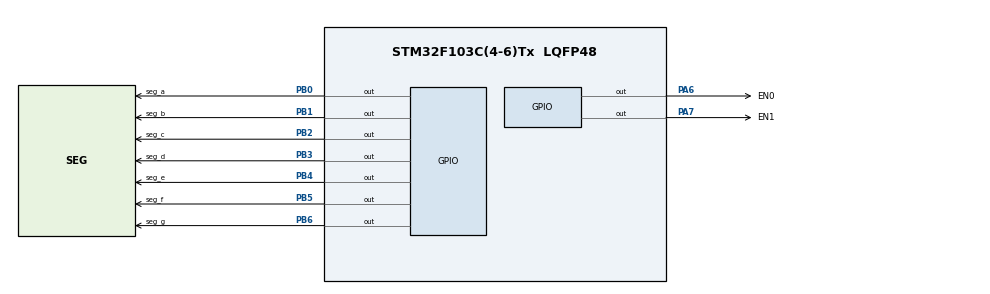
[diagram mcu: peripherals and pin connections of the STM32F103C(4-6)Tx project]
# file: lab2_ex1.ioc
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Mcu.Family=STM32F1
Mcu.Name=STM32F103C(4-6)Tx
Mcu.Package=LQFP48
NVIC.PriorityGroup=NVIC_PRIORITYGROUP_4
NVIC.TIM2_IRQn=true\:0\:0\:false\:false\:true\:true\:true\:true
PA6.GPIO_Label=EN0
PA6.Signal=GPIO_Output
PA7.GPIO_Label=EN1
PA7.Signal=GPIO_Output
PB0.GPIO_Label=seg_a
PB0.Signal=GPIO_Output
PB1.GPIO_Label=seg_b
PB1.Signal=GPIO_Output
PB2.GPIO_Label=seg_c
PB2.Signal=GPIO_Output
PB3.GPIO_Label=seg_d
PB3.Signal=GPIO_Output
PB4.GPIO_Label=seg_e
PB4.Signal=GPIO_Output
PB5.GPIO_Label=seg_f
PB5.Signal=GPIO_Output
PB6.GPIO_Label=seg_g
PB6.Signal=GPIO_Output
ProjectManager.HeapSize=0x200
ProjectManager.StackSize=0x400
ProjectManager.TargetToolchain=STM32CubeIDE
RCC.APB1Freq_Value=8000000
RCC.APB2Freq_Value=8000000
TIM2.Period=9
TIM2.Prescaler=7999
VP_TIM2_VS_ClockSourceINT.Mode=Internal
board=custom

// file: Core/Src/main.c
/* USER CODE BEGIN Header */
/**
  ******************************************************************************
  * @file           : main.c
  * @brief          : Main program body
  ******************************************************************************
  * @attention
  *
  * Copyright (c) 2022 STMicroelectronics.
  * All rights reserved.
  *
  * This software is licensed under terms that can be found in the LICENSE file
  * in the root directory of this software component.
  * If no LICENSE file comes with this software, it is provided AS-IS.
  *
  ******************************************************************************
  */
/* USER CODE END Header */
#include "main.h"

TIM_HandleTypeDef htim2;

void SystemClock_Config(void);
static void MX_GPIO_Init(void);
static void MX_TIM2_Init(void);

int main(void)
{

  /* MCU Configuration--------------------------------------------------------*/

  /* Reset of all peripherals, Initializes the Flash interface and the Systick. */
  HAL_Init();

  /* Configure the system clock */
  SystemClock_Config();

  /* Initialize all configured peripherals */
  MX_GPIO_Init();
  MX_TIM2_Init();
  /* USER CODE BEGIN 2 */
  HAL_TIM_Base_Start_IT (& htim2 );

  /* USER CODE END 2 */

  /* Infinite loop */
  while (1)
  {

  }
}

void SystemClock_Config(void)
{
  RCC_OscInitTypeDef RCC_OscInitStruct = {0};
  RCC_ClkInitTypeDef RCC_ClkInitStruct = {0};

  /** Initializes the RCC Oscillators according to the specified parameters
  * in the RCC_OscInitTypeDef structure.
  */
  RCC_OscInitStruct.OscillatorType = RCC_OSCILLATORTYPE_HSI;
  RCC_OscInitStruct.HSIState = RCC_HSI_ON;
  RCC_OscInitStruct.HSICalibrationValue = RCC_HSICALIBRATION_DEFAULT;
  RCC_OscInitStruct.PLL.PLLState = RCC_PLL_NONE;
  if (HAL_RCC_OscConfig(&RCC_OscInitStruct) != HAL_OK)
  {
    Error_Handler();
  }

  /** Initializes the CPU, AHB and APB buses clocks
  */
  RCC_ClkInitStruct.ClockType = RCC_CLOCKTYPE_HCLK|RCC_CLOCKTYPE_SYSCLK
                              |RCC_CLOCKTYPE_PCLK1|RCC_CLOCKTYPE_PCLK2;
  RCC_ClkInitStruct.SYSCLKSource = RCC_SYSCLKSOURCE_HSI;
  RCC_ClkInitStruct.AHBCLKDivider = RCC_SYSCLK_DIV1;
  RCC_ClkInitStruct.APB1CLKDivider = RCC_HCLK_DIV1;
  RCC_ClkInitStruct.APB2CLKDivider = RCC_HCLK_DIV1;

  if (HAL_RCC_ClockConfig(&RCC_ClkInitStruct, FLASH_LATENCY_0) != HAL_OK)
  {
    Error_Handler();
  }
}

static void MX_TIM2_Init(void)
{

  TIM_ClockConfigTypeDef sClockSourceConfig = {0};
  TIM_MasterConfigTypeDef sMasterConfig = {0};

  htim2.Instance = TIM2;
  htim2.Init.Prescaler = 7999;
  htim2.Init.CounterMode = TIM_COUNTERMODE_UP;
  htim2.Init.Period = 9;
  htim2.Init.ClockDivision = TIM_CLOCKDIVISION_DIV1;
  htim2.Init.AutoReloadPreload = TIM_AUTORELOAD_PRELOAD_DISABLE;
  if (HAL_TIM_Base_Init(&htim2) != HAL_OK)
  {
    Error_Handler();
  }
  sClockSourceConfig.ClockSource = TIM_CLOCKSOURCE_INTERNAL;
  if (HAL_TIM_ConfigClockSource(&htim2, &sClockSourceConfig) != HAL_OK)
  {
    Error_Handler();
  }
  sMasterConfig.MasterOutputTrigger = TIM_TRGO_RESET;
  sMasterConfig.MasterSlaveMode = TIM_MASTERSLAVEMODE_DISABLE;
  if (HAL_TIMEx_MasterConfigSynchronization(&htim2, &sMasterConfig) != HAL_OK)
  {
    Error_Handler();
  }

}

static void MX_GPIO_Init(void)
{
  GPIO_InitTypeDef GPIO_InitStruct = {0};

  /* GPIO Ports Clock Enable */
  __HAL_RCC_GPIOA_CLK_ENABLE();
  __HAL_RCC_GPIOB_CLK_ENABLE();

  /*Configure GPIO pin Output Level */
  HAL_GPIO_WritePin(GPIOA, DOT_Pin|LED_RED_Pin|EN0_Pin|EN1_Pin
                          |EN3_Pin|EN2_Pin, GPIO_PIN_RESET);

  /*Configure GPIO pin Output Level */
  HAL_GPIO_WritePin(GPIOB, seg_a_Pin|seg_b_Pin|seg_c_Pin|seg_d_Pin
                          |seg_e_Pin|seg_f_Pin|seg_g_Pin, GPIO_PIN_RESET);

  /*Configure GPIO pins : DOT_Pin LED_RED_Pin EN0_Pin EN1_Pin
                           EN3_Pin EN2_Pin */
  GPIO_InitStruct.Pin = DOT_Pin|LED_RED_Pin|EN0_Pin|EN1_Pin
                          |EN3_Pin|EN2_Pin;
  GPIO_InitStruct.Mode = GPIO_MODE_OUTPUT_PP;
  GPIO_InitStruct.Pull = GPIO_NOPULL;
  GPIO_InitStruct.Speed = GPIO_SPEED_FREQ_LOW;
  HAL_GPIO_Init(GPIOA, &GPIO_InitStruct);

  /*Configure GPIO pins : seg_a_Pin seg_b_Pin seg_c_Pin seg_d_Pin
                           seg_e_Pin seg_f_Pin seg_g_Pin */
  GPIO_InitStruct.Pin = seg_a_Pin|seg_b_Pin|seg_c_Pin|seg_d_Pin
                          |seg_e_Pin|seg_f_Pin|seg_g_Pin;
  GPIO_InitStruct.Mode = GPIO_MODE_OUTPUT_PP;
  GPIO_InitStruct.Pull = GPIO_NOPULL;
  GPIO_InitStruct.Speed = GPIO_SPEED_FREQ_LOW;
  HAL_GPIO_Init(GPIOB, &GPIO_InitStruct);

}

/* USER CODE BEGIN 4 */
void display7SEG(int num){
		if(num  == 0){
		  	  HAL_GPIO_WritePin(seg_g_GPIO_Port, seg_g_Pin, GPIO_PIN_SET);
		  	  HAL_GPIO_WritePin(seg_f_GPIO_Port, seg_f_Pin, GPIO_PIN_RESET);
		  	  HAL_GPIO_WritePin(seg_a_GPIO_Port, seg_a_Pin, GPIO_PIN_RESET);
		  	  HAL_GPIO_WritePin(seg_b_GPIO_Port, seg_b_Pin, GPIO_PIN_RESET);
		  	  HAL_GPIO_WritePin(seg_c_GPIO_Port, seg_c_Pin, GPIO_PIN_RESET);
		  	  HAL_GPIO_WritePin(seg_d_GPIO_Port, seg_d_Pin, GPIO_PIN_RESET);
		  	  HAL_GPIO_WritePin(seg_e_GPIO_Port, seg_e_Pin, GPIO_PIN_RESET);

		  	};
		  	if(num  == 1){
		  	  HAL_GPIO_WritePin(seg_g_GPIO_Port, seg_g_Pin, GPIO_PIN_SET);
		  	  HAL_GPIO_WritePin(seg_f_GPIO_Port, seg_f_Pin, GPIO_PIN_SET);
		  	  HAL_GPIO_WritePin(seg_a_GPIO_Port, seg_a_Pin, GPIO_PIN_SET);
		  	  HAL_GPIO_WritePin(seg_b_GPIO_Port, seg_b_Pin, GPIO_PIN_RESET);
		  	  HAL_GPIO_WritePin(seg_c_GPIO_Port, seg_c_Pin, GPIO_PIN_RESET);
		  	  HAL_GPIO_WritePin(seg_d_GPIO_Port, seg_d_Pin, GPIO_PIN_SET);
		  	  HAL_GPIO_WritePin(seg_e_GPIO_Port, seg_e_Pin, GPIO_PIN_SET);

		  };
		  if(num  == 2){
		  	  HAL_GPIO_WritePin(seg_g_GPIO_Port, seg_g_Pin, GPIO_PIN_RESET);
		  	  HAL_GPIO_WritePin(seg_f_GPIO_Port, seg_f_Pin, GPIO_PIN_SET);
		  	  HAL_GPIO_WritePin(seg_a_GPIO_Port, seg_a_Pin, GPIO_PIN_RESET);
		  	  HAL_GPIO_WritePin(seg_b_GPIO_Port, seg_b_Pin, GPIO_PIN_RESET);
		  	  HAL_GPIO_WritePin(seg_c_GPIO_Port, seg_c_Pin, GPIO_PIN_SET);
		  	  HAL_GPIO_WritePin(seg_d_GPIO_Port, seg_d_Pin, GPIO_PIN_RESET);
		  	  HAL_GPIO_WritePin(seg_e_GPIO_Port, seg_e_Pin, GPIO_PIN_RESET);

		  };
		  if(num  == 3){
		  	  HAL_GPIO_WritePin(seg_g_GPIO_Port, seg_g_Pin, GPIO_PIN_RESET);
		  	  HAL_GPIO_WritePin(seg_f_GPIO_Port, seg_f_Pin, GPIO_PIN_SET);
		  	  HAL_GPIO_WritePin(seg_a_GPIO_Port, seg_a_Pin, GPIO_PIN_RESET);
		  	  HAL_GPIO_WritePin(seg_b_GPIO_Port, seg_b_Pin, GPIO_PIN_RESET);
		  	  HAL_GPIO_WritePin(seg_c_GPIO_Port, seg_c_Pin, GPIO_PIN_RESET);
		  	  HAL_GPIO_WritePin(seg_d_GPIO_Port, seg_d_Pin, GPIO_PIN_RESET);
		  	  HAL_GPIO_WritePin(seg_e_GPIO_Port, seg_e_Pin, GPIO_PIN_SET);

		  }
		  if(num  == 4){
		  	  HAL_GPIO_WritePin(seg_g_GPIO_Port, seg_g_Pin, GPIO_PIN_RESET);
		  	  HAL_GPIO_WritePin(seg_f_GPIO_Port, seg_f_Pin, GPIO_PIN_RESET);
		  	  HAL_GPIO_WritePin(seg_a_GPIO_Port, seg_a_Pin, GPIO_PIN_SET);
		  	  HAL_GPIO_WritePin(seg_b_GPIO_Port, seg_b_Pin, GPIO_PIN_RESET);
		  	  HAL_GPIO_WritePin(seg_c_GPIO_Port, seg_c_Pin, GPIO_PIN_RESET);
		  	  HAL_GPIO_WritePin(seg_d_GPIO_Port, seg_d_Pin, GPIO_PIN_SET);
		  	  HAL_GPIO_WritePin(seg_e_GPIO_Port, seg_e_Pin, GPIO_PIN_SET);

		  };
		  if(num  == 5){
		  	  HAL_GPIO_WritePin(seg_g_GPIO_Port, seg_g_Pin, GPIO_PIN_RESET);
		  	  HAL_GPIO_WritePin(seg_f_GPIO_Port, seg_f_Pin, GPIO_PIN_RESET);
		  	  HAL_GPIO_WritePin(seg_a_GPIO_Port, seg_a_Pin, GPIO_PIN_RESET);
		  	  HAL_GPIO_WritePin(seg_b_GPIO_Port, seg_b_Pin, GPIO_PIN_SET);
		  	  HAL_GPIO_WritePin(seg_c_GPIO_Port, seg_c_Pin, GPIO_PIN_RESET);
		  	  HAL_GPIO_WritePin(seg_d_GPIO_Port, seg_d_Pin, GPIO_PIN_RESET);
		  	  HAL_GPIO_WritePin(seg_e_GPIO_Port, seg_e_Pin, GPIO_PIN_SET);

		  };
		  if(num  == 6){
		  	  HAL_GPIO_WritePin(seg_g_GPIO_Port, seg_g_Pin, GPIO_PIN_RESET);
		  	  HAL_GPIO_WritePin(seg_f_GPIO_Port, seg_f_Pin, GPIO_PIN_RESET);
		  	  HAL_GPIO_WritePin(seg_a_GPIO_Port, seg_a_Pin, GPIO_PIN_RESET);
		  	  HAL_GPIO_WritePin(seg_b_GPIO_Port, seg_b_Pin, GPIO_PIN_SET);
		  	  HAL_GPIO_WritePin(seg_c_GPIO_Port, seg_c_Pin, GPIO_PIN_RESET);
		  	  HAL_GPIO_WritePin(seg_d_GPIO_Port, seg_d_Pin, GPIO_PIN_RESET);
		  	  HAL_GPIO_WritePin(seg_e_GPIO_Port, seg_e_Pin, GPIO_PIN_RESET);

		  };
		  if(num  == 7){
		  	  HAL_GPIO_WritePin(seg_g_GPIO_Port, seg_g_Pin, GPIO_PIN_SET);
		  	  HAL_GPIO_WritePin(seg_f_GPIO_Port, seg_f_Pin, GPIO_PIN_SET);
		  	  HAL_GPIO_WritePin(seg_a_GPIO_Port, seg_a_Pin, GPIO_PIN_RESET);
		  	  HAL_GPIO_WritePin(seg_b_GPIO_Port, seg_b_Pin, GPIO_PIN_RESET);
		  	  HAL_GPIO_WritePin(seg_c_GPIO_Port, seg_c_Pin, GPIO_PIN_RESET);
		  	  HAL_GPIO_WritePin(seg_d_GPIO_Port, seg_d_Pin, GPIO_PIN_SET);
		  	  HAL_GPIO_WritePin(seg_e_GPIO_Port, seg_e_Pin, GPIO_PIN_SET);

		  };
		  if(num  == 8){
		  	  HAL_GPIO_WritePin(seg_g_GPIO_Port, seg_g_Pin, GPIO_PIN_RESET);
		  	  HAL_GPIO_WritePin(seg_f_GPIO_Port, seg_f_Pin, GPIO_PIN_RESET);
		  	  HAL_GPIO_WritePin(seg_a_GPIO_Port, seg_a_Pin, GPIO_PIN_RESET);
		  	  HAL_GPIO_WritePin(seg_b_GPIO_Port, seg_b_Pin, GPIO_PIN_RESET);
		  	  HAL_GPIO_WritePin(seg_c_GPIO_Port, seg_c_Pin, GPIO_PIN_RESET);
		  	  HAL_GPIO_WritePin(seg_d_GPIO_Port, seg_d_Pin, GPIO_PIN_RESET);
		  	  HAL_GPIO_WritePin(seg_e_GPIO_Port, seg_e_Pin, GPIO_PIN_RESET);

		  }
		  if(num  == 9){
		  	  HAL_GPIO_WritePin(seg_g_GPIO_Port, seg_g_Pin, GPIO_PIN_RESET);
		  	  HAL_GPIO_WritePin(seg_f_GPIO_Port, seg_f_Pin, GPIO_PIN_RESET);
		  	  HAL_GPIO_WritePin(seg_a_GPIO_Port, seg_a_Pin, GPIO_PIN_RESET);
		  	  HAL_GPIO_WritePin(seg_b_GPIO_Port, seg_b_Pin, GPIO_PIN_RESET);
		  	  HAL_GPIO_WritePin(seg_c_GPIO_Port, seg_c_Pin, GPIO_PIN_RESET);
		  	  HAL_GPIO_WritePin(seg_d_GPIO_Port, seg_d_Pin, GPIO_PIN_RESET);
		  	  HAL_GPIO_WritePin(seg_e_GPIO_Port, seg_e_Pin, GPIO_PIN_SET);

		  };
}
int counter = 50;
int led_num = 1;
void HAL_TIM_PeriodElapsedCallback( TIM_HandleTypeDef * htim )
{
	counter--;
	if( counter <= 0) {
		if (led_num == 1){
			HAL_GPIO_WritePin(EN0_GPIO_Port, EN0_Pin, GPIO_PIN_SET);
			HAL_GPIO_WritePin(EN1_GPIO_Port, EN1_Pin, GPIO_PIN_RESET);
			display7SEG(2);
		}
	if (led_num == 0){
		HAL_GPIO_WritePin(EN0_GPIO_Port, EN0_Pin, GPIO_PIN_RESET);
		HAL_GPIO_WritePin(EN1_GPIO_Port, EN1_Pin, GPIO_PIN_SET);
		display7SEG(1);
	}

	led_num = led_num ^ 1;
	counter = 50;
	}
}

/* USER CODE END 4 */

void Error_Handler(void)
{
  __disable_irq();
  while (1)
  {
  }
}
